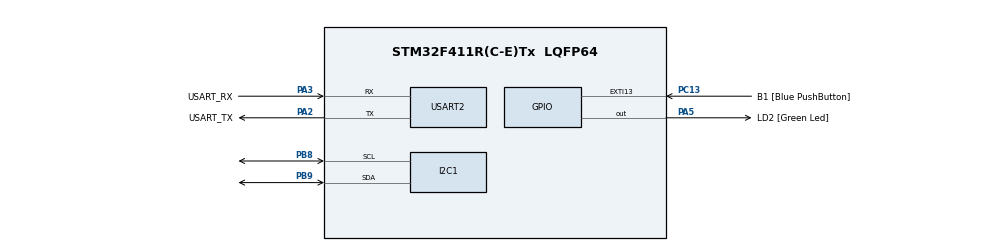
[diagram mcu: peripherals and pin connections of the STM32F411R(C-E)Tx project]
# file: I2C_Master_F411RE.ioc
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Mcu.Family=STM32F4
Mcu.Name=STM32F411R(C-E)Tx
Mcu.Package=LQFP64
NVIC.EXTI15_10_IRQn=true\:0\:0\:false\:false\:true\:true\:true\:true
NVIC.PriorityGroup=NVIC_PRIORITYGROUP_0
PA13.GPIO_Label=TMS
PA13.Mode=Serial_Wire
PA13.Signal=SYS_JTMS-SWDIO
PA14.GPIO_Label=TCK
PA14.Mode=Serial_Wire
PA14.Signal=SYS_JTCK-SWCLK
PA2.GPIO_Label=USART_TX
PA2.Mode=Asynchronous
PA2.Signal=USART2_TX
PA3.GPIO_Label=USART_RX
PA3.Mode=Asynchronous
PA3.Signal=USART2_RX
PA5.GPIO_Label=LD2 [Green Led]
PA5.Signal=GPIO_Output
PB3.GPIO_Label=SWO
PB3.Signal=SYS_JTDO-SWO
PB8.Mode=I2C
PB8.Signal=I2C1_SCL
PB9.Mode=I2C
PB9.Signal=I2C1_SDA
PC13-ANTI_TAMP.GPIO_Label=B1 [Blue PushButton]
PC13-ANTI_TAMP.GPIO_ModeDefaultEXTI=GPIO_MODE_IT_FALLING
PC13-ANTI_TAMP.Signal=GPXTI13
PC14-OSC32_IN.Mode=LSE-External-Oscillator
PC14-OSC32_IN.Signal=RCC_OSC32_IN
PC15-OSC32_OUT.Mode=LSE-External-Oscillator
PC15-OSC32_OUT.Signal=RCC_OSC32_OUT
PH0\ -\ OSC_IN.Mode=HSE-External-Clock-Source
PH0\ -\ OSC_IN.Signal=RCC_OSC_IN
PH1\ -\ OSC_OUT.Mode=HSE-External-Clock-Source
PH1\ -\ OSC_OUT.Signal=RCC_OSC_OUT
ProjectManager.HeapSize=0x200
ProjectManager.StackSize=0x400
ProjectManager.TargetToolchain=STM32CubeIDE
RCC.48MHZClocksFreq_Value=84000000
RCC.AHBFreq_Value=84000000
RCC.APB1CLKDivider=RCC_HCLK_DIV2
RCC.APB1Freq_Value=42000000
RCC.APB1TimFreq_Value=84000000
RCC.APB2Freq_Value=84000000
RCC.APB2TimFreq_Value=84000000
RCC.CortexFreq_Value=84000000
RCC.FLatency-AdvancedSettings=FLASH_LATENCY_2
RCC.HCLKFreq_Value=84000000
RCC.HSE_VALUE=8000000
RCC.HSI_VALUE=16000000
RCC.PLLN=336
RCC.PLLP=RCC_PLLP_DIV4
RCC.SYSCLKFreq_VALUE=84000000
RCC.SYSCLKSource=RCC_SYSCLKSOURCE_PLLCLK
RCC.VCOOutputFreq_Value=336000000
USART2.VirtualMode=VM_ASYNC
board=NUCLEO-F411RE

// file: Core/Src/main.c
/* USER CODE BEGIN Header */
/**
  ******************************************************************************
  * @file           : main.c
  * @brief          : Main program body - I2C Master con pulsador en PC13
  * @author         : Gustavo Escobar
  * @version        : v1.0
  * @date           : 11/09/2025
  ******************************************************************************
  * @attention
  * Este código fue generado con CubeMX y adaptado para pruebas de I2C Master
  * con STM32F411RE. Incluye integración de un pulsador en PC13 para iniciar
  * la transmisión I2C.
  ******************************************************************************
  */
/* USER CODE END Header */

#include "main.h"
#include <string.h>
#include <stdio.h>

I2C_HandleTypeDef hi2c1;
UART_HandleTypeDef huart2;

/* USER CODE BEGIN PV */
volatile uint8_t buttonPressed = 0; // bandera global

#define SLAVE_ADDRESS (0x30 << 1) // Dirección 7 bits, desplazada a 8 bits
#define TIMEOUT 100
/* USER CODE END PV */

void SystemClock_Config(void);
static void MX_GPIO_Init(void);
static void MX_I2C1_Init(void);
static void MX_USART2_UART_Init(void);
/* USER CODE BEGIN PFP */
void WaitForButtonPress(void);
/* USER CODE END PFP */

/* USER CODE BEGIN 0 */
// Callback que se ejecuta cuando hay una interrupción EXTI
void HAL_GPIO_EXTI_Callback(uint16_t GPIO_Pin)
{
    if (GPIO_Pin == GPIO_PIN_13)
    {
        buttonPressed = 1;
        char msg[] = "Interrupcion recibida en PC13\r\n";
        HAL_UART_Transmit(&huart2, (uint8_t*)msg, strlen(msg), HAL_MAX_DELAY);
    }
}

void WaitForButtonPress(void)
{

    // Espera hasta que la interrupción marque la bandera
    while (!buttonPressed)
    {
        // se queda en espera
    	char msg[] = "Sistema inicializado.\r\nPresione el pulsador para iniciar la transmision I2C...\r\n";
    	HAL_UART_Transmit(&huart2, (uint8_t*)msg, strlen(msg), HAL_MAX_DELAY);
    	HAL_Delay(3000);
    }

    char msg2[] = "Pulsador detectado, iniciando transmision I2C...\r\n";
    HAL_UART_Transmit(&huart2, (uint8_t*)msg2, strlen(msg2), HAL_MAX_DELAY);

    HAL_Delay(200); // anti-rebote
}

void I2C_ClearBusyFlagErratum(I2C_HandleTypeDef *hi2c)
{
    GPIO_InitTypeDef GPIO_InitStruct = {0};

    // 1. Resetear y deshabilitar I2C
    __HAL_RCC_I2C1_FORCE_RESET();
    __HAL_RCC_I2C1_RELEASE_RESET();
    __HAL_RCC_I2C1_CLK_DISABLE();

    // 2. Configurar PB6 (SCL) y PB7 (SDA) como GPIO open-drain
    GPIO_InitStruct.Mode  = GPIO_MODE_OUTPUT_OD;
    GPIO_InitStruct.Pull  = GPIO_PULLUP;
    GPIO_InitStruct.Speed = GPIO_SPEED_FREQ_HIGH;

    GPIO_InitStruct.Pin = GPIO_PIN_6; // SCL
    HAL_GPIO_Init(GPIOB, &GPIO_InitStruct);

    GPIO_InitStruct.Pin = GPIO_PIN_7; // SDA
    HAL_GPIO_Init(GPIOB, &GPIO_InitStruct);

    // 3. Generar 9 pulsos en SCL
    for (int i = 0; i < 9; i++)
    {
        HAL_GPIO_WritePin(GPIOB, GPIO_PIN_6, GPIO_PIN_RESET);
        HAL_Delay(1);
        HAL_GPIO_WritePin(GPIOB, GPIO_PIN_6, GPIO_PIN_SET);
        HAL_Delay(1);
    }

    // 4. Generar STOP manual
    HAL_GPIO_WritePin(GPIOB, GPIO_PIN_7, GPIO_PIN_SET); // SDA alto
    HAL_GPIO_WritePin(GPIOB, GPIO_PIN_6, GPIO_PIN_SET); // SCL alto
    HAL_Delay(1);

    // 5. Restaurar configuración de pines a función I2C
    GPIO_InitStruct.Mode = GPIO_MODE_AF_OD;
    GPIO_InitStruct.Alternate = GPIO_AF4_I2C1;

    GPIO_InitStruct.Pin = GPIO_PIN_6 | GPIO_PIN_7;
    HAL_GPIO_Init(GPIOB, &GPIO_InitStruct);

    // 6. Habilitar reloj de nuevo
    __HAL_RCC_I2C1_CLK_ENABLE();
}

/* USER CODE END 0 */

int main(void)
{
  /* USER CODE BEGIN 1 */
  uint8_t data[2] = {'A', 'B'};
  char msg[50];
  /* USER CODE END 1 */

  /* MCU Configuration--------------------------------------------------------*/

  /* Reset of all peripherals, Initializes the Flash interface and the Systick. */
  HAL_Init();

  /* Configure the system clock */
  SystemClock_Config();

  /* Initialize all configured peripherals */
  MX_GPIO_Init();
  MX_I2C1_Init();
  MX_USART2_UART_Init();
  /* USER CODE BEGIN 2 */

  strcpy(msg, "Inicio Master I2C\r\n");
  HAL_UART_Transmit(&huart2, (uint8_t*)msg, strlen(msg), HAL_MAX_DELAY);

  HAL_Delay(2000);

  // Esperar a que el usuario presione el botón antes de entrar al while
  WaitForButtonPress();
  /* USER CODE END 2 */

  /* Infinite loop */
  /* USER CODE BEGIN WHILE */
  while (1)
  {
    HAL_StatusTypeDef res = HAL_I2C_Master_Transmit(&hi2c1, SLAVE_ADDRESS, data, 2, TIMEOUT);

    if (res == HAL_OK) {
      sprintf(msg, "TX OK: %c %c\r\n", data[0], data[1]);
      HAL_UART_Transmit(&huart2, (uint8_t*)msg, strlen(msg), HAL_MAX_DELAY);
    } else {
      sprintf(msg, "Error en TX I2C: %d\r\n", res);
      HAL_UART_Transmit(&huart2, (uint8_t*)msg, strlen(msg), HAL_MAX_DELAY);
    }

    HAL_Delay(1000);
  }
  /* USER CODE END WHILE */

}

static void MX_I2C1_Init(void)
{
  /* USER CODE BEGIN I2C1_Init 0 */
	 I2C_ClearBusyFlagErratum(&hi2c1);
  /* USER CODE END I2C1_Init 0 */

  hi2c1.Instance = I2C1;
  hi2c1.Init.ClockSpeed = 100000;
  hi2c1.Init.DutyCycle = I2C_DUTYCYCLE_2;
  hi2c1.Init.OwnAddress1 = 0;
  hi2c1.Init.AddressingMode = I2C_ADDRESSINGMODE_7BIT;
  hi2c1.Init.DualAddressMode = I2C_DUALADDRESS_DISABLE;
  hi2c1.Init.OwnAddress2 = 0;
  hi2c1.Init.GeneralCallMode = I2C_GENERALCALL_DISABLE;
  hi2c1.Init.NoStretchMode = I2C_NOSTRETCH_DISABLE;
  if (HAL_I2C_Init(&hi2c1) != HAL_OK)
  {
    Error_Handler();
  }
}

static void MX_USART2_UART_Init(void)
{

  huart2.Instance = USART2;
  huart2.Init.BaudRate = 115200;
  huart2.Init.WordLength = UART_WORDLENGTH_8B;
  huart2.Init.StopBits = UART_STOPBITS_1;
  huart2.Init.Parity = UART_PARITY_NONE;
  huart2.Init.Mode = UART_MODE_TX_RX;
  huart2.Init.HwFlowCtl = UART_HWCONTROL_NONE;
  huart2.Init.OverSampling = UART_OVERSAMPLING_16;
  if (HAL_UART_Init(&huart2) != HAL_OK)
  {
    Error_Handler();
  }
}

static void MX_GPIO_Init(void)
{

  __HAL_RCC_GPIOA_CLK_ENABLE();
  __HAL_RCC_GPIOC_CLK_ENABLE();

  GPIO_InitTypeDef GPIO_InitStruct = {0};

  /* Configurar PC13 como entrada con interrupción (Botón USER) */
  GPIO_InitStruct.Pin = GPIO_PIN_13;
  GPIO_InitStruct.Mode = GPIO_MODE_IT_FALLING;
  GPIO_InitStruct.Pull = GPIO_NOPULL;
  HAL_GPIO_Init(GPIOC, &GPIO_InitStruct);

  /* Habilitar EXTI Line interrupt */
  HAL_NVIC_SetPriority(EXTI15_10_IRQn, 0, 0);
  HAL_NVIC_EnableIRQ(EXTI15_10_IRQn);

}

void SystemClock_Config(void)
{
  RCC_OscInitTypeDef RCC_OscInitStruct = {0};
  RCC_ClkInitTypeDef RCC_ClkInitStruct = {0};

  /* Oscilador HSI */
  RCC_OscInitStruct.OscillatorType = RCC_OSCILLATORTYPE_HSI;
  RCC_OscInitStruct.HSIState = RCC_HSI_ON;
  RCC_OscInitStruct.HSICalibrationValue = RCC_HSICALIBRATION_DEFAULT;
  RCC_OscInitStruct.PLL.PLLState = RCC_PLL_NONE;
  if (HAL_RCC_OscConfig(&RCC_OscInitStruct) != HAL_OK)
  {
    Error_Handler();
  }

  /* Reloj SYSCLK = HSI */
  RCC_ClkInitStruct.ClockType = RCC_CLOCKTYPE_HCLK | RCC_CLOCKTYPE_SYSCLK
                              | RCC_CLOCKTYPE_PCLK1 | RCC_CLOCKTYPE_PCLK2;
  RCC_ClkInitStruct.SYSCLKSource = RCC_SYSCLKSOURCE_HSI;
  RCC_ClkInitStruct.AHBCLKDivider = RCC_SYSCLK_DIV1;
  RCC_ClkInitStruct.APB1CLKDivider = RCC_HCLK_DIV1;
  RCC_ClkInitStruct.APB2CLKDivider = RCC_HCLK_DIV1;

  if (HAL_RCC_ClockConfig(&RCC_ClkInitStruct, FLASH_LATENCY_0) != HAL_OK)
  {
    Error_Handler();
  }
}

void Error_Handler(void)
{
  __disable_irq();
  while (1)
  {
    HAL_GPIO_TogglePin(GPIOC, GPIO_PIN_13);
    HAL_Delay(200);
  }
}

/* USER CODE BEGIN Header_EndOfFile */
/**
  ******************************************************************************
  * @file           : main.c
  * @brief          : Fin de archivo main
  ******************************************************************************
  */
/* USER CODE END Header_EndOfFile */
